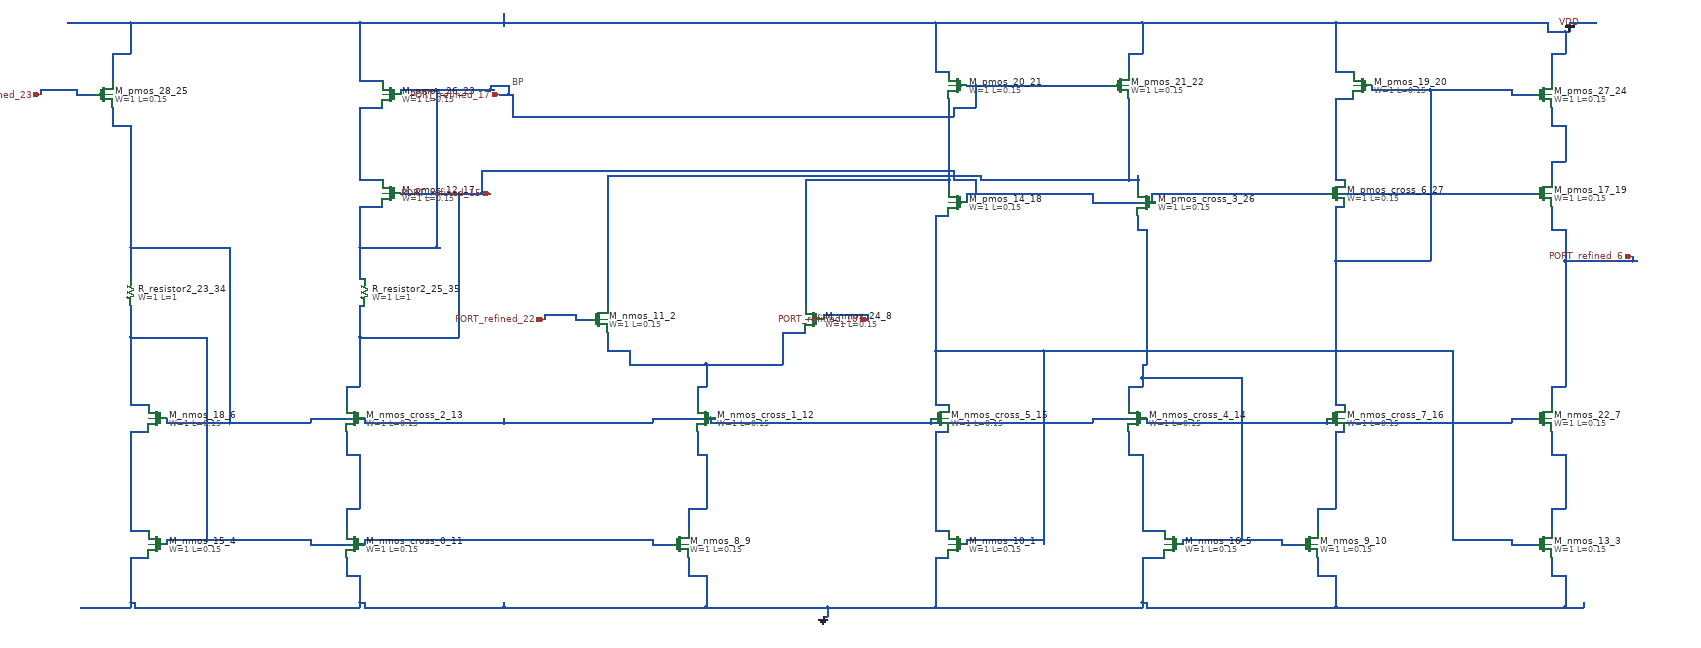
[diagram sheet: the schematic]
v {xschem version=3.4.8 file_version=1.2}
G {}
K {}
V {}
S {}
E {}
C {devices/gnd.sym} 1840 1400 0 0 {name="l_gnd_30_0" lab="GND"}
C {sky130_fd_pr/nfet3_01v8.sym} 2140 1240 0 1 {name="M_nmos_10_1"
W=1
L=0.15
body=GND
nf=1
mult=1
ad="expr('int((@nf + 1)/2) * @W / @nf * 0.29')"
pd="expr('2*int((@nf + 1)/2) * (@W / @nf + 0.29)')"
as="expr('int((@nf + 2)/2) * @W / @nf * 0.29')"
ps="expr('2*int((@nf + 2)/2) * (@W / @nf + 0.29)')"
nrd="expr('0.29 / @W ')" nrs="expr('0.29 / @W ')"
sa=0 sb=0 sd=0
model=nfet_01v8
spiceprefix=X
}
C {sky130_fd_pr/nfet3_01v8.sym} 1340 740 0 0 {name="M_nmos_11_2"
W=1
L=0.15
body=GND
nf=1
mult=1
ad="expr('int((@nf + 1)/2) * @W / @nf * 0.29')"
pd="expr('2*int((@nf + 1)/2) * (@W / @nf + 0.29)')"
as="expr('int((@nf + 2)/2) * @W / @nf * 0.29')"
ps="expr('2*int((@nf + 2)/2) * (@W / @nf + 0.29)')"
nrd="expr('0.29 / @W ')" nrs="expr('0.29 / @W ')"
sa=0 sb=0 sd=0
model=nfet_01v8
spiceprefix=X
}
C {sky130_fd_pr/nfet3_01v8.sym} 3440 1240 0 0 {name="M_nmos_13_3"
W=1
L=0.15
body=GND
nf=1
mult=1
ad="expr('int((@nf + 1)/2) * @W / @nf * 0.29')"
pd="expr('2*int((@nf + 1)/2) * (@W / @nf + 0.29)')"
as="expr('int((@nf + 2)/2) * @W / @nf * 0.29')"
ps="expr('2*int((@nf + 2)/2) * (@W / @nf + 0.29)')"
nrd="expr('0.29 / @W ')" nrs="expr('0.29 / @W ')"
sa=0 sb=0 sd=0
model=nfet_01v8
spiceprefix=X
}
C {sky130_fd_pr/nfet3_01v8.sym} 360 1240 0 1 {name="M_nmos_15_4"
W=1
L=0.15
body=GND
nf=1
mult=1
ad="expr('int((@nf + 1)/2) * @W / @nf * 0.29')"
pd="expr('2*int((@nf + 1)/2) * (@W / @nf + 0.29)')"
as="expr('int((@nf + 2)/2) * @W / @nf * 0.29')"
ps="expr('2*int((@nf + 2)/2) * (@W / @nf + 0.29)')"
nrd="expr('0.29 / @W ')" nrs="expr('0.29 / @W ')"
sa=0 sb=0 sd=0
model=nfet_01v8
spiceprefix=X
}
C {sky130_fd_pr/nfet3_01v8.sym} 2620 1240 0 1 {name="M_nmos_16_5"
W=1
L=0.15
body=GND
nf=1
mult=1
ad="expr('int((@nf + 1)/2) * @W / @nf * 0.29')"
pd="expr('2*int((@nf + 1)/2) * (@W / @nf + 0.29)')"
as="expr('int((@nf + 2)/2) * @W / @nf * 0.29')"
ps="expr('2*int((@nf + 2)/2) * (@W / @nf + 0.29)')"
nrd="expr('0.29 / @W ')" nrs="expr('0.29 / @W ')"
sa=0 sb=0 sd=0
model=nfet_01v8
spiceprefix=X
}
C {sky130_fd_pr/nfet3_01v8.sym} 360 960 0 1 {name="M_nmos_18_6"
W=1
L=0.15
body=GND
nf=1
mult=1
ad="expr('int((@nf + 1)/2) * @W / @nf * 0.29')"
pd="expr('2*int((@nf + 1)/2) * (@W / @nf + 0.29)')"
as="expr('int((@nf + 2)/2) * @W / @nf * 0.29')"
ps="expr('2*int((@nf + 2)/2) * (@W / @nf + 0.29)')"
nrd="expr('0.29 / @W ')" nrs="expr('0.29 / @W ')"
sa=0 sb=0 sd=0
model=nfet_01v8
spiceprefix=X
}
C {sky130_fd_pr/nfet3_01v8.sym} 3440 960 0 0 {name="M_nmos_22_7"
W=1
L=0.15
body=GND
nf=1
mult=1
ad="expr('int((@nf + 1)/2) * @W / @nf * 0.29')"
pd="expr('2*int((@nf + 1)/2) * (@W / @nf + 0.29)')"
as="expr('int((@nf + 2)/2) * @W / @nf * 0.29')"
ps="expr('2*int((@nf + 2)/2) * (@W / @nf + 0.29)')"
nrd="expr('0.29 / @W ')" nrs="expr('0.29 / @W ')"
sa=0 sb=0 sd=0
model=nfet_01v8
spiceprefix=X
}
C {sky130_fd_pr/nfet3_01v8.sym} 1820 740 0 1 {name="M_nmos_24_8"
W=1
L=0.15
body=GND
nf=1
mult=1
ad="expr('int((@nf + 1)/2) * @W / @nf * 0.29')"
pd="expr('2*int((@nf + 1)/2) * (@W / @nf + 0.29)')"
as="expr('int((@nf + 2)/2) * @W / @nf * 0.29')"
ps="expr('2*int((@nf + 2)/2) * (@W / @nf + 0.29)')"
nrd="expr('0.29 / @W ')" nrs="expr('0.29 / @W ')"
sa=0 sb=0 sd=0
model=nfet_01v8
spiceprefix=X
}
C {sky130_fd_pr/nfet3_01v8.sym} 1520 1240 0 0 {name="M_nmos_8_9"
W=1
L=0.15
body=GND
nf=1
mult=1
ad="expr('int((@nf + 1)/2) * @W / @nf * 0.29')"
pd="expr('2*int((@nf + 1)/2) * (@W / @nf + 0.29)')"
as="expr('int((@nf + 2)/2) * @W / @nf * 0.29')"
ps="expr('2*int((@nf + 2)/2) * (@W / @nf + 0.29)')"
nrd="expr('0.29 / @W ')" nrs="expr('0.29 / @W ')"
sa=0 sb=0 sd=0
model=nfet_01v8
spiceprefix=X
}
C {sky130_fd_pr/nfet3_01v8.sym} 2920 1240 0 0 {name="M_nmos_9_10"
W=1
L=0.15
body=GND
nf=1
mult=1
ad="expr('int((@nf + 1)/2) * @W / @nf * 0.29')"
pd="expr('2*int((@nf + 1)/2) * (@W / @nf + 0.29)')"
as="expr('int((@nf + 2)/2) * @W / @nf * 0.29')"
ps="expr('2*int((@nf + 2)/2) * (@W / @nf + 0.29)')"
nrd="expr('0.29 / @W ')" nrs="expr('0.29 / @W ')"
sa=0 sb=0 sd=0
model=nfet_01v8
spiceprefix=X
}
C {sky130_fd_pr/nfet3_01v8.sym} 800 1240 0 1 {name="M_nmos_cross_0_11"
W=1
L=0.15
body=GND
nf=1
mult=1
ad="expr('int((@nf + 1)/2) * @W / @nf * 0.29')"
pd="expr('2*int((@nf + 1)/2) * (@W / @nf + 0.29)')"
as="expr('int((@nf + 2)/2) * @W / @nf * 0.29')"
ps="expr('2*int((@nf + 2)/2) * (@W / @nf + 0.29)')"
nrd="expr('0.29 / @W ')" nrs="expr('0.29 / @W ')"
sa=0 sb=0 sd=0
model=nfet_01v8
spiceprefix=X
}
C {sky130_fd_pr/nfet3_01v8.sym} 1580 960 0 1 {name="M_nmos_cross_1_12"
W=1
L=0.15
body=GND
nf=1
mult=1
ad="expr('int((@nf + 1)/2) * @W / @nf * 0.29')"
pd="expr('2*int((@nf + 1)/2) * (@W / @nf + 0.29)')"
as="expr('int((@nf + 2)/2) * @W / @nf * 0.29')"
ps="expr('2*int((@nf + 2)/2) * (@W / @nf + 0.29)')"
nrd="expr('0.29 / @W ')" nrs="expr('0.29 / @W ')"
sa=0 sb=0 sd=0
model=nfet_01v8
spiceprefix=X
}
C {sky130_fd_pr/nfet3_01v8.sym} 800 960 0 1 {name="M_nmos_cross_2_13"
W=1
L=0.15
body=GND
nf=1
mult=1
ad="expr('int((@nf + 1)/2) * @W / @nf * 0.29')"
pd="expr('2*int((@nf + 1)/2) * (@W / @nf + 0.29)')"
as="expr('int((@nf + 2)/2) * @W / @nf * 0.29')"
ps="expr('2*int((@nf + 2)/2) * (@W / @nf + 0.29)')"
nrd="expr('0.29 / @W ')" nrs="expr('0.29 / @W ')"
sa=0 sb=0 sd=0
model=nfet_01v8
spiceprefix=X
}
C {sky130_fd_pr/nfet3_01v8.sym} 2540 960 0 1 {name="M_nmos_cross_4_14"
W=1
L=0.15
body=GND
nf=1
mult=1
ad="expr('int((@nf + 1)/2) * @W / @nf * 0.29')"
pd="expr('2*int((@nf + 1)/2) * (@W / @nf + 0.29)')"
as="expr('int((@nf + 2)/2) * @W / @nf * 0.29')"
ps="expr('2*int((@nf + 2)/2) * (@W / @nf + 0.29)')"
nrd="expr('0.29 / @W ')" nrs="expr('0.29 / @W ')"
sa=0 sb=0 sd=0
model=nfet_01v8
spiceprefix=X
}
C {sky130_fd_pr/nfet3_01v8.sym} 2100 960 0 0 {name="M_nmos_cross_5_15"
W=1
L=0.15
body=GND
nf=1
mult=1
ad="expr('int((@nf + 1)/2) * @W / @nf * 0.29')"
pd="expr('2*int((@nf + 1)/2) * (@W / @nf + 0.29)')"
as="expr('int((@nf + 2)/2) * @W / @nf * 0.29')"
ps="expr('2*int((@nf + 2)/2) * (@W / @nf + 0.29)')"
nrd="expr('0.29 / @W ')" nrs="expr('0.29 / @W ')"
sa=0 sb=0 sd=0
model=nfet_01v8
spiceprefix=X
}
C {sky130_fd_pr/nfet3_01v8.sym} 2980 960 0 0 {name="M_nmos_cross_7_16"
W=1
L=0.15
body=GND
nf=1
mult=1
ad="expr('int((@nf + 1)/2) * @W / @nf * 0.29')"
pd="expr('2*int((@nf + 1)/2) * (@W / @nf + 0.29)')"
as="expr('int((@nf + 2)/2) * @W / @nf * 0.29')"
ps="expr('2*int((@nf + 2)/2) * (@W / @nf + 0.29)')"
nrd="expr('0.29 / @W ')" nrs="expr('0.29 / @W ')"
sa=0 sb=0 sd=0
model=nfet_01v8
spiceprefix=X
}
C {sky130_fd_pr/pfet3_01v8.sym} 880 460 0 1 {name="M_pmos_12_17"
W=1
L=0.15
body=VDD
nf=1
mult=1
ad="expr('int((@nf + 1)/2) * @W / @nf * 0.29')"
pd="expr('2*int((@nf + 1)/2) * (@W / @nf + 0.29)')"
as="expr('int((@nf + 2)/2) * @W / @nf * 0.29')"
ps="expr('2*int((@nf + 2)/2) * (@W / @nf + 0.29)')"
nrd="expr('0.29 / @W ')" nrs="expr('0.29 / @W ')"
sa=0 sb=0 sd=0
model=pfet_01v8
spiceprefix=X
}
C {sky130_fd_pr/pfet3_01v8.sym} 2140 480 0 1 {name="M_pmos_14_18"
W=1
L=0.15
body=VDD
nf=1
mult=1
ad="expr('int((@nf + 1)/2) * @W / @nf * 0.29')"
pd="expr('2*int((@nf + 1)/2) * (@W / @nf + 0.29)')"
as="expr('int((@nf + 2)/2) * @W / @nf * 0.29')"
ps="expr('2*int((@nf + 2)/2) * (@W / @nf + 0.29)')"
nrd="expr('0.29 / @W ')" nrs="expr('0.29 / @W ')"
sa=0 sb=0 sd=0
model=pfet_01v8
spiceprefix=X
}
C {sky130_fd_pr/pfet3_01v8.sym} 3440 460 0 0 {name="M_pmos_17_19"
W=1
L=0.15
body=VDD
nf=1
mult=1
ad="expr('int((@nf + 1)/2) * @W / @nf * 0.29')"
pd="expr('2*int((@nf + 1)/2) * (@W / @nf + 0.29)')"
as="expr('int((@nf + 2)/2) * @W / @nf * 0.29')"
ps="expr('2*int((@nf + 2)/2) * (@W / @nf + 0.29)')"
nrd="expr('0.29 / @W ')" nrs="expr('0.29 / @W ')"
sa=0 sb=0 sd=0
model=pfet_01v8
spiceprefix=X
}
C {sky130_fd_pr/pfet3_01v8.sym} 3040 220 0 1 {name="M_pmos_19_20"
W=1
L=0.15
body=VDD
nf=1
mult=1
ad="expr('int((@nf + 1)/2) * @W / @nf * 0.29')"
pd="expr('2*int((@nf + 1)/2) * (@W / @nf + 0.29)')"
as="expr('int((@nf + 2)/2) * @W / @nf * 0.29')"
ps="expr('2*int((@nf + 2)/2) * (@W / @nf + 0.29)')"
nrd="expr('0.29 / @W ')" nrs="expr('0.29 / @W ')"
sa=0 sb=0 sd=0
model=pfet_01v8
spiceprefix=X
}
C {sky130_fd_pr/pfet3_01v8.sym} 2140 220 0 1 {name="M_pmos_20_21"
W=1
L=0.15
body=VDD
nf=1
mult=1
ad="expr('int((@nf + 1)/2) * @W / @nf * 0.29')"
pd="expr('2*int((@nf + 1)/2) * (@W / @nf + 0.29)')"
as="expr('int((@nf + 2)/2) * @W / @nf * 0.29')"
ps="expr('2*int((@nf + 2)/2) * (@W / @nf + 0.29)')"
nrd="expr('0.29 / @W ')" nrs="expr('0.29 / @W ')"
sa=0 sb=0 sd=0
model=pfet_01v8
spiceprefix=X
}
C {sky130_fd_pr/pfet3_01v8.sym} 2500 220 0 0 {name="M_pmos_21_22"
W=1
L=0.15
body=VDD
nf=1
mult=1
ad="expr('int((@nf + 1)/2) * @W / @nf * 0.29')"
pd="expr('2*int((@nf + 1)/2) * (@W / @nf + 0.29)')"
as="expr('int((@nf + 2)/2) * @W / @nf * 0.29')"
ps="expr('2*int((@nf + 2)/2) * (@W / @nf + 0.29)')"
nrd="expr('0.29 / @W ')" nrs="expr('0.29 / @W ')"
sa=0 sb=0 sd=0
model=pfet_01v8
spiceprefix=X
}
C {sky130_fd_pr/pfet3_01v8.sym} 880 240 0 1 {name="M_pmos_26_23"
W=1
L=0.15
body=VDD
nf=1
mult=1
ad="expr('int((@nf + 1)/2) * @W / @nf * 0.29')"
pd="expr('2*int((@nf + 1)/2) * (@W / @nf + 0.29)')"
as="expr('int((@nf + 2)/2) * @W / @nf * 0.29')"
ps="expr('2*int((@nf + 2)/2) * (@W / @nf + 0.29)')"
nrd="expr('0.29 / @W ')" nrs="expr('0.29 / @W ')"
sa=0 sb=0 sd=0
model=pfet_01v8
spiceprefix=X
}
C {sky130_fd_pr/pfet3_01v8.sym} 3440 240 0 0 {name="M_pmos_27_24"
W=1
L=0.15
body=VDD
nf=1
mult=1
ad="expr('int((@nf + 1)/2) * @W / @nf * 0.29')"
pd="expr('2*int((@nf + 1)/2) * (@W / @nf + 0.29)')"
as="expr('int((@nf + 2)/2) * @W / @nf * 0.29')"
ps="expr('2*int((@nf + 2)/2) * (@W / @nf + 0.29)')"
nrd="expr('0.29 / @W ')" nrs="expr('0.29 / @W ')"
sa=0 sb=0 sd=0
model=pfet_01v8
spiceprefix=X
}
C {sky130_fd_pr/pfet3_01v8.sym} 240 240 0 0 {name="M_pmos_28_25"
W=1
L=0.15
body=VDD
nf=1
mult=1
ad="expr('int((@nf + 1)/2) * @W / @nf * 0.29')"
pd="expr('2*int((@nf + 1)/2) * (@W / @nf + 0.29)')"
as="expr('int((@nf + 2)/2) * @W / @nf * 0.29')"
ps="expr('2*int((@nf + 2)/2) * (@W / @nf + 0.29)')"
nrd="expr('0.29 / @W ')" nrs="expr('0.29 / @W ')"
sa=0 sb=0 sd=0
model=pfet_01v8
spiceprefix=X
}
C {sky130_fd_pr/pfet3_01v8.sym} 2560 480 0 1 {name="M_pmos_cross_3_26"
W=1
L=0.15
body=VDD
nf=1
mult=1
ad="expr('int((@nf + 1)/2) * @W / @nf * 0.29')"
pd="expr('2*int((@nf + 1)/2) * (@W / @nf + 0.29)')"
as="expr('int((@nf + 2)/2) * @W / @nf * 0.29')"
ps="expr('2*int((@nf + 2)/2) * (@W / @nf + 0.29)')"
nrd="expr('0.29 / @W ')" nrs="expr('0.29 / @W ')"
sa=0 sb=0 sd=0
model=pfet_01v8
spiceprefix=X
}
C {sky130_fd_pr/pfet3_01v8.sym} 2980 460 0 0 {name="M_pmos_cross_6_27"
W=1
L=0.15
body=VDD
nf=1
mult=1
ad="expr('int((@nf + 1)/2) * @W / @nf * 0.29')"
pd="expr('2*int((@nf + 1)/2) * (@W / @nf + 0.29)')"
as="expr('int((@nf + 2)/2) * @W / @nf * 0.29')"
ps="expr('2*int((@nf + 2)/2) * (@W / @nf + 0.29)')"
nrd="expr('0.29 / @W ')" nrs="expr('0.29 / @W ')"
sa=0 sb=0 sd=0
model=pfet_01v8
spiceprefix=X
}
C {devices/ipin.sym} 1940 740 0 0 {name="p_port_29_28" lab="PORT_refined_10"}
C {devices/ipin.sym} 1220 740 0 0 {name="p_port_31_29" lab="PORT_refined_22"}
C {devices/ipin.sym} 3640 600 0 0 {name="p_port_32_30" lab="PORT_refined_6"}
C {devices/ipin.sym} 100 240 0 0 {name="p_port_33_31" lab="PORT_refined_23"}
C {devices/ipin.sym} 1100 460 0 0 {name="p_port_40_32" lab="PORT_refined_15"}
C {devices/ipin.sym} 1120 240 0 0 {name="p_port_41_33" lab="PORT_refined_17"}
T {BP} 1150 200 0 0 0.25 0.25 {}
C {sky130_fd_pr/res_generic_po.sym} 300 680 2 0 {name="R_resistor2_23_34"
W=1
L=1
model=res_generic_po
spiceprefix=X
mult=1}
C {sky130_fd_pr/res_generic_po.sym} 820 680 2 0 {name="R_resistor2_25_35"
W=1
L=1
model=res_generic_po
spiceprefix=X
mult=1}
C {devices/vdd.sym} 3500 100 0 0 {name="l_vdd_34_36" lab="VDD"}
N 1840 1400 1850 1400 {}
N 190 1380 300 1380 {}
N 310 1380 810 1380 {}
N 820 1380 1130 1380 {}
N 1130 1380 1580 1380 {}
N 1580 1380 1850 1380 {}
N 1850 1380 2090 1380 {}
N 2090 1380 2550 1380 {}
N 2560 1380 2980 1380 {}
N 2980 1380 3490 1380 {}
N 3490 1380 3530 1380 {}
N 300 1370 310 1370 {}
N 810 1370 820 1370 {}
N 2550 1370 2560 1370 {}
N 780 1310 810 1310 {}
N 1540 1310 1580 1310 {}
N 2940 1310 2980 1310 {}
N 3460 1310 3490 1310 {}
N 300 1270 340 1270 {}
N 2090 1270 2120 1270 {}
N 2550 1270 2600 1270 {}
N 300 1380 300 1370 {}
N 300 1370 300 1270 {}
N 310 1380 310 1370 {}
N 780 1310 780 1270 {}
N 810 1380 810 1370 {}
N 810 1370 810 1310 {}
N 820 1380 820 1370 {}
N 1130 1380 1130 1370 {}
N 1540 1310 1540 1270 {}
N 1580 1380 1580 1310 {}
N 1850 1400 1850 1380 {}
N 2090 1380 2090 1270 {}
N 2550 1380 2550 1370 {}
N 2550 1370 2550 1270 {}
N 2560 1380 2560 1370 {}
N 2940 1310 2940 1270 {}
N 2980 1380 2980 1310 {}
N 3460 1310 3460 1270 {}
N 3490 1380 3490 1310 {}
N 3530 1380 3530 1370 {}
N 300 1210 340 1210 {}
N 300 990 340 990 {}
N 300 1210 300 990 {}
N 1840 730 1940 730 {}
N 1840 740 1840 730 {}
N 1940 740 1940 730 {}
N 1540 1160 1580 1160 {}
N 1560 1040 1580 1040 {}
N 1540 1210 1540 1160 {}
N 1560 1040 1560 990 {}
N 1580 1160 1580 1040 {}
N 2940 1160 2980 1160 {}
N 2980 990 3000 990 {}
N 2940 1210 2940 1160 {}
N 2980 1160 2980 990 {}
N 3370 1240 3420 1240 {}
N 2160 1230 2330 1230 {}
N 3240 1230 3370 1230 {}
N 2090 930 2120 930 {}
N 2090 810 2330 810 {}
N 2330 810 3240 810 {}
N 2090 510 2120 510 {}
N 2090 930 2090 810 {}
N 2090 810 2090 510 {}
N 2160 1240 2160 1230 {}
N 2330 1240 2330 1230 {}
N 2330 1230 2330 810 {}
N 3240 1230 3240 810 {}
N 3370 1240 3370 1230 {}
N 780 1160 810 1160 {}
N 780 1040 810 1040 {}
N 780 1210 780 1160 {}
N 780 1040 780 990 {}
N 810 1160 810 1040 {}
N 780 890 810 890 {}
N 810 780 1030 780 {}
N 810 710 820 710 {}
N 2440 480 2570 480 {}
N 2570 480 2580 480 {}
N 900 460 1030 460 {}
N 1030 460 1080 460 {}
N 1080 460 1100 460 {}
N 2160 460 2180 460 {}
N 2180 460 2440 460 {}
N 2570 460 2960 460 {}
N 2960 460 3420 460 {}
N 2130 430 2180 430 {}
N 1080 410 2130 410 {}
N 780 930 780 890 {}
N 810 890 810 780 {}
N 810 780 810 710 {}
N 1030 780 1030 460 {}
N 1080 460 1080 410 {}
N 2130 430 2130 410 {}
N 2160 480 2160 460 {}
N 2180 460 2180 430 {}
N 2440 480 2440 460 {}
N 2570 480 2570 460 {}
N 2980 930 3000 930 {}
N 2980 610 3190 610 {}
N 2980 490 3000 490 {}
N 3370 240 3420 240 {}
N 3060 230 3190 230 {}
N 3190 230 3370 230 {}
N 2980 930 2980 610 {}
N 2980 610 2980 490 {}
N 3060 230 3060 220 {}
N 3190 610 3190 230 {}
N 3370 240 3370 230 {}
N 810 650 820 650 {}
N 810 580 980 580 {}
N 980 580 990 580 {}
N 810 490 860 490 {}
N 1150 290 2130 290 {}
N 2130 270 2180 270 {}
N 1120 240 1140 240 {}
N 1140 240 1150 240 {}
N 900 230 980 230 {}
N 980 230 1100 230 {}
N 1100 230 1110 230 {}
N 1100 220 1140 220 {}
N 2160 220 2180 220 {}
N 2180 220 2480 220 {}
N 810 650 810 580 {}
N 810 580 810 490 {}
N 900 240 900 230 {}
N 980 580 980 230 {}
N 1100 230 1100 220 {}
N 1140 240 1140 220 {}
N 1150 290 1150 240 {}
N 2130 290 2130 270 {}
N 2180 270 2180 220 {}
N 810 430 860 430 {}
N 810 270 860 270 {}
N 810 430 810 270 {}
N 3460 390 3490 390 {}
N 3460 310 3490 310 {}
N 3460 430 3460 390 {}
N 3460 310 3460 270 {}
N 3490 390 3490 310 {}
N 700 1240 820 1240 {}
N 1460 1240 1500 1240 {}
N 380 1230 470 1230 {}
N 470 1230 700 1230 {}
N 820 1230 1460 1230 {}
N 300 930 340 930 {}
N 300 780 470 780 {}
N 300 930 300 780 {}
N 300 780 300 710 {}
N 380 1240 380 1230 {}
N 470 1230 470 780 {}
N 700 1240 700 1230 {}
N 820 1240 820 1230 {}
N 1460 1240 1460 1230 {}
N 2980 430 3000 430 {}
N 2980 250 3020 250 {}
N 2980 430 2980 250 {}
N 810 210 860 210 {}
N 2090 190 2120 190 {}
N 2980 190 3020 190 {}
N 260 150 300 150 {}
N 2520 150 2550 150 {}
N 3460 150 3490 150 {}
N 3450 100 3490 100 {}
N 3490 100 3500 100 {}
N 160 80 300 80 {}
N 300 80 810 80 {}
N 810 80 1130 80 {}
N 1130 80 2090 80 {}
N 2090 80 2550 80 {}
N 2550 80 2980 80 {}
N 2980 80 3450 80 {}
N 3500 80 3560 80 {}
N 260 210 260 150 {}
N 300 150 300 80 {}
N 810 210 810 80 {}
N 1130 90 1130 80 {}
N 1130 80 1130 60 {}
N 2090 190 2090 80 {}
N 2520 190 2520 150 {}
N 2550 150 2550 80 {}
N 2980 190 2980 80 {}
N 3450 100 3450 80 {}
N 3460 210 3460 150 {}
N 3490 150 3490 100 {}
N 3500 100 3500 80 {}
N 1290 740 1320 740 {}
N 1220 730 1290 730 {}
N 1220 740 1220 730 {}
N 1290 740 1290 730 {}
N 180 240 220 240 {}
N 100 230 180 230 {}
N 100 240 100 230 {}
N 180 240 180 230 {}
N 1800 430 2120 430 {}
N 1800 710 1800 430 {}
N 2120 450 2120 430 {}
N 2120 430 2120 250 {}
N 2190 430 2520 430 {}
N 2520 430 2540 430 {}
N 1360 420 2190 420 {}
N 1360 710 1360 420 {}
N 2190 430 2190 420 {}
N 2520 430 2520 250 {}
N 2540 450 2540 430 {}
N 2540 430 2540 420 {}
N 2550 1210 2600 1210 {}
N 2520 1040 2550 1040 {}
N 2520 1040 2520 990 {}
N 2550 1210 2550 1040 {}
N 2860 1240 2900 1240 {}
N 2640 1230 2770 1230 {}
N 2770 1230 2860 1230 {}
N 2520 890 2550 890 {}
N 2550 870 2770 870 {}
N 2550 840 2560 840 {}
N 2540 540 2560 540 {}
N 2520 930 2520 890 {}
N 2540 540 2540 510 {}
N 2550 890 2550 870 {}
N 2550 870 2550 840 {}
N 2560 840 2560 540 {}
N 2640 1240 2640 1230 {}
N 2770 1230 2770 870 {}
N 2860 1240 2860 1230 {}
N 380 970 520 970 {}
N 520 970 700 970 {}
N 820 970 1130 970 {}
N 1130 970 1460 970 {}
N 1590 970 2080 970 {}
N 2080 970 2440 970 {}
N 2560 970 2960 970 {}
N 2960 970 3370 970 {}
N 700 960 820 960 {}
N 1460 960 1590 960 {}
N 1590 960 1600 960 {}
N 2440 960 2560 960 {}
N 3370 960 3420 960 {}
N 300 580 520 580 {}
N 260 310 300 310 {}
N 260 310 260 270 {}
N 300 650 300 580 {}
N 300 580 300 310 {}
N 380 970 380 960 {}
N 520 970 520 580 {}
N 700 970 700 960 {}
N 820 970 820 960 {}
N 1130 970 1130 960 {}
N 1460 970 1460 960 {}
N 1590 970 1590 960 {}
N 2080 970 2080 960 {}
N 2440 970 2440 960 {}
N 2560 970 2560 960 {}
N 2960 970 2960 960 {}
N 3370 970 3370 960 {}
N 3460 890 3490 890 {}
N 3490 610 3640 610 {}
N 3640 610 3650 610 {}
N 3460 540 3490 540 {}
N 3460 930 3460 890 {}
N 3460 540 3460 490 {}
N 3490 890 3490 610 {}
N 3490 610 3490 540 {}
N 3640 610 3640 600 {}
N 2090 1210 2120 1210 {}
N 2090 990 2120 990 {}
N 2090 1210 2090 990 {}
N 3460 1160 3490 1160 {}
N 3460 1040 3490 1040 {}
N 3460 1210 3460 1160 {}
N 3460 1040 3460 990 {}
N 3490 1160 3490 1040 {}
N 1560 890 1580 890 {}
N 1410 840 1580 840 {}
N 1580 840 1750 840 {}
N 1360 810 1410 810 {}
N 1750 770 1800 770 {}
N 1360 810 1360 770 {}
N 1410 840 1410 810 {}
N 1560 930 1560 890 {}
N 1580 890 1580 840 {}
N 1750 840 1750 770 {}
